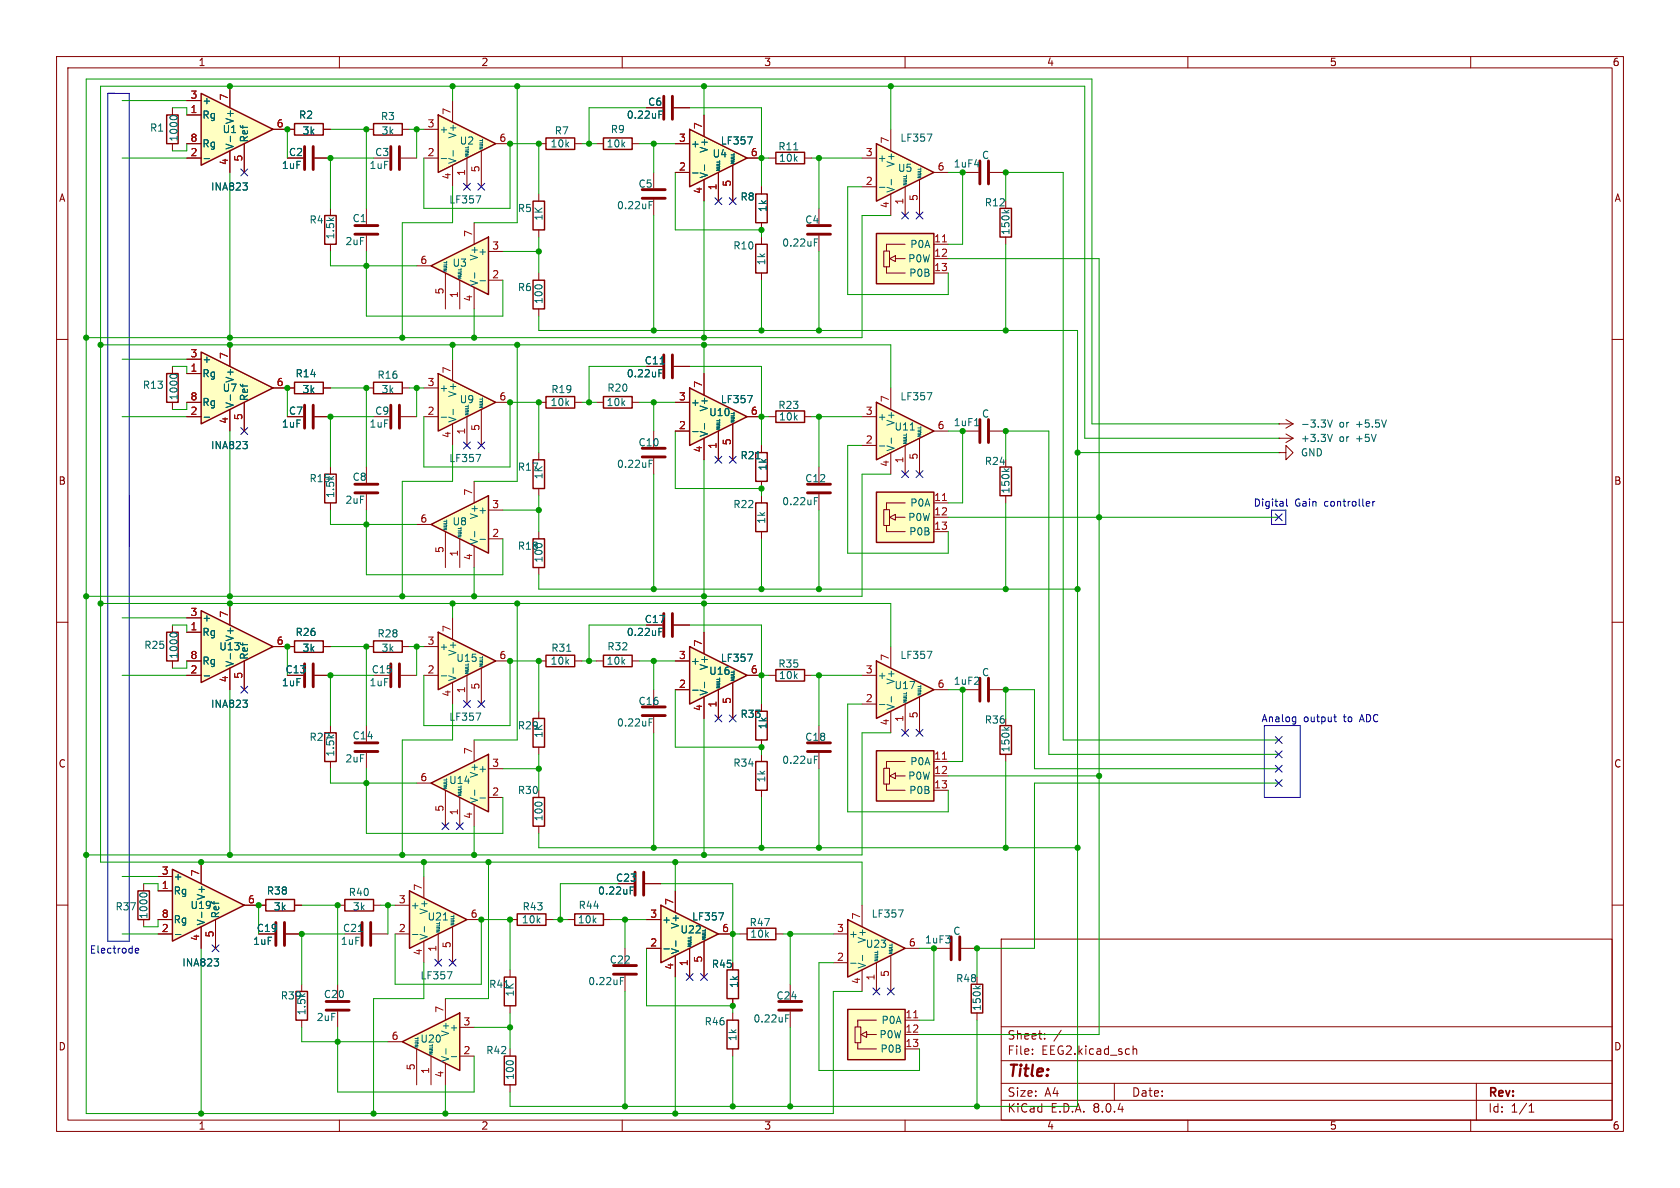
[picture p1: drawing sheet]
<svg xmlns="http://www.w3.org/2000/svg" width="297mm" height="210mm" viewBox="0 0 297 210" stroke-linecap="round" stroke-linejoin="round" font-family="sans-serif">
<defs><g id="words">
<text font-size="2.8" fill="#840000" x="178" y="190.9">Title:</text>
<g font-size="2.1" fill="#840000">
<text x="178" y="184">Sheet:</text>
<text x="178" y="186.7">File:</text>
<text x="184.1" y="186.7">EEG2.kicad_sch</text>
<text x="178" y="196.9">KiCad</text>
<text x="178" y="194.1">Size:</text>
<text x="184.7" y="194.1">A4</text>
<text x="185.7" y="196.9">E.D.A.</text>
<text x="193.3" y="196.9">8.0.4</text>
<text x="200" y="194.1">Date:</text>
<text x="263" y="194.3">Rev:</text>
<text x="263" y="196.9">Id:</text>
<text x="267.1" y="196.9">1/1</text>
</g>
<g font-size="1.8" fill="#840000">
<text x="35" y="11.9">1</text>
<text x="85" y="11.9">2</text>
<text x="135" y="11.9">3</text>
<text x="185" y="11.9">4</text>
<text x="235" y="11.9">5</text>
<text x="285" y="11.9">6</text>
<text x="114.5" y="18.9">C6</text>
<text x="51" y="27.8">C2</text>
<text x="10.3" y="35.9">A</text>
<text x="285.3" y="35.9">A</text>
<text x="113.9" y="64.6">C11</text>
<text x="51" y="73.5">C7</text>
<text x="10.3" y="85.9">B</text>
<text x="285.3" y="85.9">B</text>
<text x="113.9" y="110.3">C17</text>
<text x="50.4" y="119.2">C13</text>
<text x="10.3" y="135.9">C</text>
<text x="285.3" y="135.9">C</text>
<text x="108.8" y="156.1">C23</text>
<text x="45.3" y="164.9">C19</text>
<text x="10.3" y="185.9">D</text>
<text x="285.3" y="185.9">D</text>
<text x="35" y="199.9">1</text>
<text x="85" y="199.9">2</text>
<text x="135" y="199.9">3</text>
<text x="185" y="199.9">4</text>
<text x="235" y="199.9">5</text>
<text x="285" y="199.9">6</text>
</g>
<g font-size="1.8" fill="#a90000">
<text x="33.6" y="17.5">3</text>
<text x="40.4" y="17.9" transform="rotate(-90 40.4 17.9)">7</text>
<text x="33.6" y="20.1">1</text>
<text x="48.8" y="22.6">6</text>
<text x="75.5" y="22.6">3</text>
<text x="79.8" y="20.4" transform="rotate(-90 79.8 20.4)">7</text>
<text x="124.2" y="22.9" transform="rotate(-90 124.2 22.9)">7</text>
<text x="33.6" y="27.7">2</text>
<text x="33.6" y="25.1">8</text>
<text x="40.4" y="29.3" transform="rotate(-90 40.4 29.3)">4</text>
<text x="42.9" y="28.6" transform="rotate(-90 42.9 28.6)">5</text>
<text x="75.5" y="27.7">2</text>
<text x="88.2" y="25.1">6</text>
<text x="119.9" y="25.1">3</text>
<text x="132.6" y="27.7">6</text>
<text x="153" y="27.7">3</text>
<text x="157.2" y="25.5" transform="rotate(-90 157.2 25.5)">7</text>
<text x="79.8" y="31.8" transform="rotate(-90 79.8 31.8)">4</text>
<text x="82.3" y="31.2" transform="rotate(-90 82.3 31.2)">1</text>
<text x="84.8" y="30.6" transform="rotate(-90 84.8 30.6)">5</text>
<text x="119.9" y="30.2">2</text>
<text x="124.2" y="34.4" transform="rotate(-90 124.2 34.4)">4</text>
<text x="126.7" y="33.7" transform="rotate(-90 126.7 33.7)">1</text>
<text x="129.3" y="33.1" transform="rotate(-90 129.3 33.1)">5</text>
<text x="153" y="32.8">2</text>
<text x="162.3" y="35.6" transform="rotate(-90 162.3 35.6)">5</text>
<text x="165.7" y="30.2">6</text>
<text x="83.6" y="42" transform="rotate(-90 83.6 42)">7</text>
<text x="157.2" y="36.9" transform="rotate(-90 157.2 36.9)">4</text>
<text x="159.8" y="36.3" transform="rotate(-90 159.8 36.3)">1</text>
<text x="74.2" y="46.7">6</text>
<text x="86.9" y="44.2">3</text>
<text x="165.1" y="42.9">11</text>
<text x="165.1" y="45.5">12</text>
<text x="78.5" y="52.1" transform="rotate(-90 78.5 52.1)">5</text>
<text x="81" y="52.8" transform="rotate(-90 81 52.8)">1</text>
<text x="83.6" y="53.4" transform="rotate(-90 83.6 53.4)">4</text>
<text x="86.9" y="49.3">2</text>
<text x="165.1" y="48">13</text>
<text x="33.6" y="65.8">1</text>
<text x="33.6" y="63.2">3</text>
<text x="40.4" y="63.6" transform="rotate(-90 40.4 63.6)">7</text>
<text x="33.6" y="70.9">8</text>
<text x="48.8" y="68.3">6</text>
<text x="75.5" y="68.3">3</text>
<text x="79.8" y="66.1" transform="rotate(-90 79.8 66.1)">7</text>
<text x="88.2" y="70.9">6</text>
<text x="119.9" y="70.9">3</text>
<text x="124.2" y="68.7" transform="rotate(-90 124.2 68.7)">7</text>
<text x="157.2" y="71.2" transform="rotate(-90 157.2 71.2)">7</text>
<text x="33.6" y="73.4">2</text>
<text x="40.4" y="75" transform="rotate(-90 40.4 75)">4</text>
<text x="42.9" y="74.4" transform="rotate(-90 42.9 74.4)">5</text>
<text x="75.5" y="73.4">2</text>
<text x="79.8" y="77.5" transform="rotate(-90 79.8 77.5)">4</text>
<text x="82.3" y="76.9" transform="rotate(-90 82.3 76.9)">1</text>
<text x="84.8" y="76.3" transform="rotate(-90 84.8 76.3)">5</text>
<text x="119.9" y="75.9">2</text>
<text x="132.6" y="73.4">6</text>
<text x="153" y="73.4">3</text>
<text x="165.7" y="75.9">6</text>
<text x="124.2" y="80.1" transform="rotate(-90 124.2 80.1)">4</text>
<text x="126.7" y="79.4" transform="rotate(-90 126.7 79.4)">1</text>
<text x="129.3" y="78.8" transform="rotate(-90 129.3 78.8)">5</text>
<text x="153" y="78.5">2</text>
<text x="157.2" y="82.6" transform="rotate(-90 157.2 82.6)">4</text>
<text x="159.8" y="82" transform="rotate(-90 159.8 82)">1</text>
<text x="162.3" y="81.4" transform="rotate(-90 162.3 81.4)">5</text>
<text x="83.6" y="87.7" transform="rotate(-90 83.6 87.7)">7</text>
<text x="86.9" y="89.9">3</text>
<text x="165.1" y="88.6">11</text>
<text x="74.2" y="92.5">6</text>
<text x="86.9" y="95">2</text>
<text x="165.1" y="91.2">12</text>
<text x="165.1" y="93.7">13</text>
<text x="78.5" y="97.9" transform="rotate(-90 78.5 97.9)">5</text>
<text x="81" y="98.5" transform="rotate(-90 81 98.5)">1</text>
<text x="83.6" y="99.1" transform="rotate(-90 83.6 99.1)">4</text>
<text x="33.6" y="111.5">1</text>
<text x="33.6" y="109">3</text>
<text x="40.4" y="109.3" transform="rotate(-90 40.4 109.3)">7</text>
<text x="79.8" y="111.8" transform="rotate(-90 79.8 111.8)">7</text>
<text x="33.6" y="119.1">2</text>
<text x="33.6" y="116.6">8</text>
<text x="48.8" y="114">6</text>
<text x="75.5" y="119.1">2</text>
<text x="75.5" y="114">3</text>
<text x="88.2" y="116.6">6</text>
<text x="119.9" y="116.6">3</text>
<text x="124.2" y="114.4" transform="rotate(-90 124.2 114.4)">7</text>
<text x="132.6" y="119.1">6</text>
<text x="153" y="119.1">3</text>
<text x="157.2" y="116.9" transform="rotate(-90 157.2 116.9)">7</text>
<text x="40.4" y="120.7" transform="rotate(-90 40.4 120.7)">4</text>
<text x="42.9" y="120.1" transform="rotate(-90 42.9 120.1)">5</text>
<text x="79.8" y="123.3" transform="rotate(-90 79.8 123.3)">4</text>
<text x="82.3" y="122.6" transform="rotate(-90 82.3 122.6)">1</text>
<text x="84.8" y="122" transform="rotate(-90 84.8 122)">5</text>
<text x="119.9" y="121.7">2</text>
<text x="124.2" y="125.8" transform="rotate(-90 124.2 125.8)">4</text>
<text x="126.7" y="125.2" transform="rotate(-90 126.7 125.2)">1</text>
<text x="129.3" y="124.5" transform="rotate(-90 129.3 124.5)">5</text>
<text x="153" y="124.2">2</text>
<text x="165.7" y="121.7">6</text>
<text x="157.2" y="128.3" transform="rotate(-90 157.2 128.3)">4</text>
<text x="159.8" y="127.7" transform="rotate(-90 159.8 127.7)">1</text>
<text x="162.3" y="127.1" transform="rotate(-90 162.3 127.1)">5</text>
<text x="83.6" y="133.4" transform="rotate(-90 83.6 133.4)">7</text>
<text x="86.9" y="135.6">3</text>
<text x="165.1" y="134.4">11</text>
<text x="165.1" y="136.9">12</text>
<text x="74.2" y="138.2">6</text>
<text x="78.5" y="143.6" transform="rotate(-90 78.5 143.6)">5</text>
<text x="86.9" y="140.7">2</text>
<text x="165.1" y="139.4">13</text>
<text x="81" y="144.2" transform="rotate(-90 81 144.2)">1</text>
<text x="83.6" y="144.9" transform="rotate(-90 83.6 144.9)">4</text>
<text x="28.5" y="154.7">3</text>
<text x="35.3" y="155" transform="rotate(-90 35.3 155)">7</text>
<text x="28.5" y="157.2">1</text>
<text x="43.7" y="159.8">6</text>
<text x="70.4" y="159.8">3</text>
<text x="74.7" y="157.6" transform="rotate(-90 74.7 157.6)">7</text>
<text x="119.1" y="160.1" transform="rotate(-90 119.1 160.1)">7</text>
<text x="28.5" y="164.8">2</text>
<text x="28.5" y="162.3">8</text>
<text x="35.3" y="166.4" transform="rotate(-90 35.3 166.4)">4</text>
<text x="37.8" y="165.8" transform="rotate(-90 37.8 165.8)">5</text>
<text x="70.4" y="164.8">2</text>
<text x="79.8" y="167.7" transform="rotate(-90 79.8 167.7)">5</text>
<text x="83.1" y="162.3">6</text>
<text x="114.9" y="167.4">2</text>
<text x="114.9" y="162.3">3</text>
<text x="127.6" y="164.8">6</text>
<text x="147.9" y="164.8">3</text>
<text x="152.1" y="162.6" transform="rotate(-90 152.1 162.6)">7</text>
<text x="160.6" y="167.4">6</text>
<text x="74.7" y="169" transform="rotate(-90 74.7 169)">4</text>
<text x="77.2" y="168.3" transform="rotate(-90 77.2 168.3)">1</text>
<text x="119.1" y="171.5" transform="rotate(-90 119.1 171.5)">4</text>
<text x="121.7" y="170.9" transform="rotate(-90 121.7 170.9)">1</text>
<text x="124.2" y="170.3" transform="rotate(-90 124.2 170.3)">5</text>
<text x="147.9" y="169.9">2</text>
<text x="154.7" y="173.4" transform="rotate(-90 154.7 173.4)">1</text>
<text x="157.2" y="172.8" transform="rotate(-90 157.2 172.8)">5</text>
<text x="78.5" y="179.1" transform="rotate(-90 78.5 179.1)">7</text>
<text x="152.1" y="174.1" transform="rotate(-90 152.1 174.1)">4</text>
<text x="69.1" y="183.9">6</text>
<text x="81.8" y="181.4">3</text>
<text x="160" y="180.1">11</text>
<text x="160" y="182.6">12</text>
<text x="160" y="185.2">13</text>
<text x="73.4" y="189.3" transform="rotate(-90 73.4 189.3)">5</text>
<text x="75.9" y="189.9" transform="rotate(-90 75.9 189.9)">1</text>
<text x="78.5" y="190.6" transform="rotate(-90 78.5 190.6)">4</text>
<text x="81.8" y="186.4">2</text>
</g>
<g font-size="1.8" fill="#006464">
<text x="26.4" y="23.5">R1</text>
<text x="35.7" y="21.2">Rg</text>
<text x="35.7" y="18.6">+</text>
<text x="39.3" y="23.7">U1</text>
<text x="41.5" y="22" transform="rotate(-90 41.5 22)">V+</text>
<text x="52.8" y="21.2">R2</text>
<text x="53.4" y="24">3k</text>
<text x="67.2" y="21.4">R3</text>
<text x="67.4" y="24">3k</text>
<text x="77.6" y="23.7">+</text>
<text x="98" y="24">R7</text>
<text x="107.9" y="23.7">R9</text>
<text x="110.7" y="21.2">0.22uF</text>
<text x="31.6" y="25.1" transform="rotate(-90 31.6 25.1)">1000</text>
<text x="35.7" y="26.3">Rg</text>
<text x="41.5" y="26.5" transform="rotate(-90 41.5 26.5)">V-</text>
<text x="44" y="25.3" transform="rotate(-90 44 25.3)">Ref</text>
<text x="66.2" y="27.8">C3</text>
<text x="80.9" y="29.1" transform="rotate(-90 80.9 29.1)">V-</text>
<text x="80.9" y="24.6" transform="rotate(-90 80.9 24.6)">V+</text>
<text x="81.2" y="25.8">U2</text>
<text x="97.2" y="26.3">10k</text>
<text x="107.1" y="26.3">10k</text>
<text x="122" y="26.3">+</text>
<text x="125.3" y="27.1" transform="rotate(-90 125.3 27.1)">V+</text>
<text x="125.9" y="28">U4</text>
<text x="127.3" y="25.8">LF357</text>
<text x="137.5" y="26.8">R11</text>
<text x="137.6" y="28.8">10k</text>
<text x="155.1" y="28.8">+</text>
<text x="158.3" y="29.7" transform="rotate(-90 158.3 29.7)">V+</text>
<text x="159.1" y="25.2">LF357</text>
<text x="168.5" y="29.8">1uF4</text>
<text x="173.5" y="28.3">C</text>
<text x="37.2" y="33.9">INA823</text>
<text x="49.7" y="30.1">1uF</text>
<text x="65.2" y="30.1">1uF</text>
<text x="112.8" y="33.4">C5</text>
<text x="125.3" y="31.6" transform="rotate(-90 125.3 31.6)">V-</text>
<text x="130.8" y="35.7">R8</text>
<text x="158.3" y="34.2" transform="rotate(-90 158.3 34.2)">V-</text>
<text x="158.6" y="30.6">U5</text>
<text x="54.6" y="39.7">R4</text>
<text x="62.2" y="39.5">C1</text>
<text x="79.3" y="36.2">LF357</text>
<text x="91.4" y="37.7">R5</text>
<text x="96.1" y="39.1" transform="rotate(-90 96.1 39.1)">1K</text>
<text x="109" y="37.2">0.22uF</text>
<text x="135.7" y="37.6" transform="rotate(-90 135.7 37.6)">1k</text>
<text x="142.2" y="39.7">C4</text>
<text x="174" y="36.7">R12</text>
<text x="178.7" y="41.6" transform="rotate(-90 178.7 41.6)">150k</text>
<text x="59.3" y="42.4" transform="rotate(-90 59.3 42.4)">1.5k</text>
<text x="61" y="43.5">2uF</text>
<text x="79.9" y="47.3">U3</text>
<text x="84.5" y="45.3">+</text>
<text x="84.7" y="46.2" transform="rotate(-90 84.7 46.2)">V+</text>
<text x="129.5" y="44.3">R10</text>
<text x="135.5" y="47" transform="rotate(-90 135.5 47)">1k</text>
<text x="138.2" y="43.8">0.22uF</text>
<text x="160.5" y="46.6">P0W</text>
<text x="160.8" y="44">P0A</text>
<text x="84.7" y="50.7" transform="rotate(-90 84.7 50.7)">V-</text>
<text x="91.4" y="51.7">R6</text>
<text x="96.1" y="53.8" transform="rotate(-90 96.1 53.8)">100</text>
<text x="160.6" y="49.1">P0B</text>
<text x="35.7" y="64.4">+</text>
<text x="25.2" y="68.9">R13</text>
<text x="31.6" y="70.9" transform="rotate(-90 31.6 70.9)">1000</text>
<text x="35.7" y="66.9">Rg</text>
<text x="35.7" y="72">Rg</text>
<text x="39.3" y="69.4">U7</text>
<text x="41.5" y="67.8" transform="rotate(-90 41.5 67.8)">V+</text>
<text x="44" y="71" transform="rotate(-90 44 71)">Ref</text>
<text x="52.2" y="66.9">R14</text>
<text x="53.4" y="69.7">3k</text>
<text x="66.6" y="67.2">R16</text>
<text x="67.4" y="69.7">3k</text>
<text x="77.6" y="69.4">+</text>
<text x="80.9" y="70.3" transform="rotate(-90 80.9 70.3)">V+</text>
<text x="81.2" y="71.5">U9</text>
<text x="97.2" y="72">10k</text>
<text x="97.4" y="69.7">R19</text>
<text x="107.1" y="72">10k</text>
<text x="107.3" y="69.4">R20</text>
<text x="110.7" y="66.9">0.22uF</text>
<text x="122" y="72">+</text>
<text x="127.3" y="71.5">LF357</text>
<text x="159.1" y="71">LF357</text>
<text x="41.5" y="72.3" transform="rotate(-90 41.5 72.3)">V-</text>
<text x="49.7" y="75.8">1uF</text>
<text x="65.2" y="75.8">1uF</text>
<text x="66.2" y="73.5">C9</text>
<text x="80.9" y="74.8" transform="rotate(-90 80.9 74.8)">V-</text>
<text x="125.3" y="73.8">U10</text>
<text x="125.3" y="77.3" transform="rotate(-90 125.3 77.3)">V-</text>
<text x="125.3" y="72.8" transform="rotate(-90 125.3 72.8)">V+</text>
<text x="137.5" y="72.5">R23</text>
<text x="137.6" y="74.5">10k</text>
<text x="155.1" y="74.5">+</text>
<text x="158" y="76.3">U11</text>
<text x="158.3" y="75.4" transform="rotate(-90 158.3 75.4)">V+</text>
<text x="168.5" y="75.5">1uF1</text>
<text x="173.5" y="74">C</text>
<text x="229.9" y="75.8">-3.3V</text>
<text x="236.7" y="75.8">or</text>
<text x="239.8" y="75.8">+5.5V</text>
<text x="37.2" y="79.6">INA823</text>
<text x="79.3" y="81.9">LF357</text>
<text x="91.4" y="83.4">R17</text>
<text x="109" y="82.9">0.22uF</text>
<text x="112.8" y="79.1">C10</text>
<text x="130.8" y="81.4">R21</text>
<text x="135.7" y="83.3" transform="rotate(-90 135.7 83.3)">1k</text>
<text x="158.3" y="79.9" transform="rotate(-90 158.3 79.9)">V-</text>
<text x="174" y="82.4">R24</text>
<text x="229.9" y="80.9">GND</text>
<text x="229.9" y="78.3">+3.3V</text>
<text x="236.7" y="78.3">or</text>
<text x="239.8" y="78.3">+5V</text>
<text x="54.6" y="85.4">R15</text>
<text x="59.3" y="88.1" transform="rotate(-90 59.3 88.1)">1.5k</text>
<text x="61" y="89.3">2uF</text>
<text x="62.2" y="85.2">C8</text>
<text x="96.1" y="84.8" transform="rotate(-90 96.1 84.8)">1K</text>
<text x="138.2" y="89.5">0.22uF</text>
<text x="142.2" y="85.4">C12</text>
<text x="160.8" y="89.8">P0A</text>
<text x="178.7" y="87.4" transform="rotate(-90 178.7 87.4)">150k</text>
<text x="79.9" y="93.1">U8</text>
<text x="84.5" y="91">+</text>
<text x="84.7" y="91.9" transform="rotate(-90 84.7 91.9)">V+</text>
<text x="129.5" y="90">R22</text>
<text x="135.5" y="92.7" transform="rotate(-90 135.5 92.7)">1k</text>
<text x="160.5" y="92.3">P0W</text>
<text x="160.6" y="94.8">P0B</text>
<text x="84.7" y="96.4" transform="rotate(-90 84.7 96.4)">V-</text>
<text x="91.4" y="97.4">R18</text>
<text x="96.1" y="99.6" transform="rotate(-90 96.1 99.6)">100</text>
<text x="35.7" y="112.6">Rg</text>
<text x="35.7" y="110.1">+</text>
<text x="41.5" y="113.5" transform="rotate(-90 41.5 113.5)">V+</text>
<text x="52.2" y="112.6">R26</text>
<text x="66.6" y="112.9">R28</text>
<text x="110.7" y="112.6">0.22uF</text>
<text x="25.4" y="114.9">R25</text>
<text x="31.6" y="116.6" transform="rotate(-90 31.6 116.6)">1000</text>
<text x="35.7" y="117.7">Rg</text>
<text x="38.7" y="115.2">U13</text>
<text x="41.5" y="118" transform="rotate(-90 41.5 118)">V-</text>
<text x="44" y="116.7" transform="rotate(-90 44 116.7)">Ref</text>
<text x="53.4" y="115.4">3k</text>
<text x="65.6" y="119.2">C15</text>
<text x="67.4" y="115.4">3k</text>
<text x="77.6" y="115.2">+</text>
<text x="80.6" y="117.2">U15</text>
<text x="80.9" y="116" transform="rotate(-90 80.9 116)">V+</text>
<text x="97.2" y="117.7">10k</text>
<text x="97.4" y="115.4">R31</text>
<text x="107.1" y="117.7">10k</text>
<text x="107.3" y="115.2">R32</text>
<text x="122" y="117.7">+</text>
<text x="125.3" y="119.5">U16</text>
<text x="125.3" y="118.6" transform="rotate(-90 125.3 118.6)">V+</text>
<text x="127.3" y="117.2">LF357</text>
<text x="137.5" y="118.2">R35</text>
<text x="159.1" y="116.7">LF357</text>
<text x="173.5" y="119.7">C</text>
<text x="37.2" y="125.3">INA823</text>
<text x="49.7" y="121.5">1uF</text>
<text x="65.2" y="121.5">1uF</text>
<text x="80.9" y="120.5" transform="rotate(-90 80.9 120.5)">V-</text>
<text x="112.8" y="124.8">C16</text>
<text x="125.3" y="123.1" transform="rotate(-90 125.3 123.1)">V-</text>
<text x="137.6" y="120.2">10k</text>
<text x="155.1" y="120.2">+</text>
<text x="158" y="122">U17</text>
<text x="158.3" y="125.6" transform="rotate(-90 158.3 125.6)">V-</text>
<text x="158.3" y="121.1" transform="rotate(-90 158.3 121.1)">V+</text>
<text x="168.5" y="121.3">1uF2</text>
<text x="54.6" y="131.2">R27</text>
<text x="62.2" y="130.9">C14</text>
<text x="79.3" y="127.6">LF357</text>
<text x="91.4" y="129.1">R29</text>
<text x="96.1" y="130.5" transform="rotate(-90 96.1 130.5)">1K</text>
<text x="109" y="128.6">0.22uF</text>
<text x="130.8" y="127.1">R33</text>
<text x="135.7" y="129" transform="rotate(-90 135.7 129)">1k</text>
<text x="142.2" y="131.2">C18</text>
<text x="174" y="128.1">R36</text>
<text x="59.3" y="133.8" transform="rotate(-90 59.3 133.8)">1.5k</text>
<text x="61" y="135">2uF</text>
<text x="84.5" y="136.8">+</text>
<text x="84.7" y="137.6" transform="rotate(-90 84.7 137.6)">V+</text>
<text x="129.5" y="135.7">R34</text>
<text x="138.2" y="135.2">0.22uF</text>
<text x="160.8" y="135.5">P0A</text>
<text x="178.7" y="133.1" transform="rotate(-90 178.7 133.1)">150k</text>
<text x="79.3" y="138.8">U14</text>
<text x="84.7" y="142.1" transform="rotate(-90 84.7 142.1)">V-</text>
<text x="91.4" y="140.6">R30</text>
<text x="135.5" y="138.4" transform="rotate(-90 135.5 138.4)">1k</text>
<text x="160.5" y="138">P0W</text>
<text x="160.6" y="140.6">P0B</text>
<text x="96.1" y="145.3" transform="rotate(-90 96.1 145.3)">100</text>
<text x="30.6" y="155.8">+</text>
<text x="20.3" y="161.1">R37</text>
<text x="30.6" y="158.3">Rg</text>
<text x="33.6" y="160.9">U19</text>
<text x="36.4" y="159.2" transform="rotate(-90 36.4 159.2)">V+</text>
<text x="47.1" y="158.3">R38</text>
<text x="48.3" y="161.1">3k</text>
<text x="61.6" y="158.6">R40</text>
<text x="62.3" y="161.1">3k</text>
<text x="72.5" y="160.9">+</text>
<text x="75.8" y="161.7" transform="rotate(-90 75.8 161.7)">V+</text>
<text x="92.3" y="161.1">R43</text>
<text x="102.2" y="160.9">R44</text>
<text x="105.6" y="158.3">0.22uF</text>
<text x="26.3" y="162.6" transform="rotate(-90 26.3 162.6)">1000</text>
<text x="30.6" y="163.4">Rg</text>
<text x="36.4" y="163.7" transform="rotate(-90 36.4 163.7)">V-</text>
<text x="39" y="162.4" transform="rotate(-90 39 162.4)">Ref</text>
<text x="44.7" y="167.2">1uF</text>
<text x="60.2" y="167.2">1uF</text>
<text x="60.5" y="164.9">C21</text>
<text x="75.5" y="162.9">U21</text>
<text x="75.8" y="166.2" transform="rotate(-90 75.8 166.2)">V-</text>
<text x="92.2" y="163.4">10k</text>
<text x="102.1" y="163.4">10k</text>
<text x="117" y="163.4">+</text>
<text x="120.2" y="165.2">U22</text>
<text x="120.2" y="164.3" transform="rotate(-90 120.2 164.3)">V+</text>
<text x="122.2" y="162.9">LF357</text>
<text x="132.4" y="163.9">R47</text>
<text x="132.5" y="166">10k</text>
<text x="150" y="166">+</text>
<text x="153" y="167.7">U23</text>
<text x="153.3" y="166.8" transform="rotate(-90 153.3 166.8)">V+</text>
<text x="154" y="162.4">LF357</text>
<text x="163.4" y="167">1uF3</text>
<text x="168.4" y="165.5">C</text>
<text x="32.1" y="171">INA823</text>
<text x="74.2" y="173.3">LF357</text>
<text x="107.7" y="170.5">C22</text>
<text x="120.2" y="168.8" transform="rotate(-90 120.2 168.8)">V-</text>
<text x="125.7" y="171.3">R45</text>
<text x="153.3" y="171.3" transform="rotate(-90 153.3 171.3)">V-</text>
<text x="168.9" y="173.8">R48</text>
<text x="49.5" y="176.9">R39</text>
<text x="54.2" y="179.6" transform="rotate(-90 54.2 179.6)">1.5k</text>
<text x="57.2" y="176.6">C20</text>
<text x="86.4" y="174.9">R41</text>
<text x="91" y="176.3" transform="rotate(-90 91 176.3)">1K</text>
<text x="103.9" y="174.3">0.22uF</text>
<text x="130.7" y="174.7" transform="rotate(-90 130.7 174.7)">1k</text>
<text x="137.2" y="176.9">C24</text>
<text x="173.6" y="178.8" transform="rotate(-90 173.6 178.8)">150k</text>
<text x="55.9" y="180.7">2uF</text>
<text x="74.2" y="184.5">U20</text>
<text x="79.4" y="182.5">+</text>
<text x="79.6" y="183.3" transform="rotate(-90 79.6 183.3)">V+</text>
<text x="124.5" y="181.5">R46</text>
<text x="130.4" y="184.1" transform="rotate(-90 130.4 184.1)">1k</text>
<text x="133.1" y="180.9">0.22uF</text>
<text x="155.4" y="183.7">P0W</text>
<text x="155.7" y="181.2">P0A</text>
<text x="79.6" y="187.8" transform="rotate(-90 79.6 187.8)">V-</text>
<text x="85.9" y="186.5">R42</text>
<text x="91" y="191" transform="rotate(-90 91 191)">100</text>
<text x="155.6" y="186.3">P0B</text>
</g>
<g font-size="1.8" fill="#0000c2">
<text x="221.5" y="89.8">Digital</text>
<text x="228.9" y="89.8">Gain</text>
<text x="234.2" y="89.8">controller</text>
<text x="222.9" y="127.9">Analog</text>
<text x="230.4" y="127.9">output</text>
<text x="237.7" y="127.9">to</text>
<text x="240.7" y="127.9">ADC</text>
<text x="15.8" y="168.8">Electrode</text>
</g>
<g font-size=".7" fill="#006464">
<text x="83" y="27.8" transform="rotate(-90 83 27.8)">NULL</text>
<text x="85.6" y="26.5" transform="rotate(-90 85.6 26.5)">NULL</text>
<text x="130" y="29.1" transform="rotate(-90 130 29.1)">NULL</text>
<text x="127.5" y="30.4" transform="rotate(-90 127.5 30.4)">NULL</text>
<text x="160.5" y="32.9" transform="rotate(-90 160.5 32.9)">NULL</text>
<text x="163" y="31.6" transform="rotate(-90 163 31.6)">NULL</text>
<text x="79.2" y="48.1" transform="rotate(-90 79.2 48.1)">NULL</text>
<text x="81.8" y="49.4" transform="rotate(-90 81.8 49.4)">NULL</text>
<text x="83" y="73.5" transform="rotate(-90 83 73.5)">NULL</text>
<text x="85.6" y="72.3" transform="rotate(-90 85.6 72.3)">NULL</text>
<text x="127.5" y="76.1" transform="rotate(-90 127.5 76.1)">NULL</text>
<text x="130" y="74.8" transform="rotate(-90 130 74.8)">NULL</text>
<text x="163" y="77.3" transform="rotate(-90 163 77.3)">NULL</text>
<text x="160.5" y="78.6" transform="rotate(-90 160.5 78.6)">NULL</text>
<text x="79.2" y="93.9" transform="rotate(-90 79.2 93.9)">NULL</text>
<text x="81.8" y="95.1" transform="rotate(-90 81.8 95.1)">NULL</text>
<text x="83" y="119.3" transform="rotate(-90 83 119.3)">NULL</text>
<text x="85.6" y="118" transform="rotate(-90 85.6 118)">NULL</text>
<text x="127.5" y="121.8" transform="rotate(-90 127.5 121.8)">NULL</text>
<text x="130" y="120.5" transform="rotate(-90 130 120.5)">NULL</text>
<text x="160.5" y="124.3" transform="rotate(-90 160.5 124.3)">NULL</text>
<text x="163" y="123.1" transform="rotate(-90 163 123.1)">NULL</text>
<text x="79.2" y="139.6" transform="rotate(-90 79.2 139.6)">NULL</text>
<text x="81.8" y="140.8" transform="rotate(-90 81.8 140.8)">NULL</text>
<text x="78" y="165" transform="rotate(-90 78 165)">NULL</text>
<text x="80.5" y="163.7" transform="rotate(-90 80.5 163.7)">NULL</text>
<text x="122.4" y="167.5" transform="rotate(-90 122.4 167.5)">NULL</text>
<text x="124.9" y="166.2" transform="rotate(-90 124.9 166.2)">NULL</text>
<text x="155.4" y="170.1" transform="rotate(-90 155.4 170.1)">NULL</text>
<text x="158" y="168.8" transform="rotate(-90 158 168.8)">NULL</text>
<text x="74.1" y="185.3" transform="rotate(-90 74.1 185.3)">NULL</text>
<text x="76.7" y="186.6" transform="rotate(-90 76.7 186.6)">NULL</text>
</g>
</g></defs>
<g fill="none" stroke="#840000" stroke-width=".18">
<path d="M10 10h277v190h-277zM12 12h273v186h-273zM60 10v2M110 10v2M160 10v2M210 10v2M260 10v2M10 60h2M285 60h2M226.1 77.5h.1M226.1 74.9h.1M226.1 77.5h2.5"/>
<path d="M226.1 74.9h2.5M227.3 76.7l1.3 .8M227.3 74.2l1.3 .7M228.6 77.5l-1.3 .7M228.6 74.9l-1.3 .8M226.1 80h1.2v-1.3l1.3 1.3-1.3 1.3v-1.3M226.1 80h.1M10 110h2M285 110h2M10 160h2M285 160h2M177 166h108v32h-108z"/>
<path d="M60 198v2M110 198v2M160 198v2M177 194.5h108M177 191.5h108M177 187.5h108M177 181.5h108M182.5 186.3v.1M182.5 185.5v.1M184.7 183.6v.1M184.7 182.8v.1M187.6 182.1l-1.3 2"/>
<path d="M197 191.5v3M200.3 184.9v1.5M200.3 185.5l.2-.1 .4 .1 .1 .9M210 198v2M260 198v2M261 191.5v6.5M270.3 196.6h.9M270.3 195.5l.4-.4v1.5"/>
</g>
<path d="M234.7 74.2l.4 1.3 .4-1.3M235.5 76.8l-.4 1.2M245.1 74.2l-.4 1.3" fill="none" stroke="#006464" stroke-width=".18"/>
<path d="M35.6 108l12.7 6.3-12.7 6.4z" fill="#ffffc2"/>
<path d="M106.7 24.4h5.1v2h-5.1zM176.8 82.6h2v5h-2zM29.5 111.8h2v5h-2zM35.6 108l12.7 6.3-12.7 6.4zM57.4 129.5h2v5.1h-2zM133.6 134.6h2v5.1h-2zM133.6 125.7h2v5.1h-2zM47 159h5.1v2h-5.1zM52.3 175.3h2.1v5h-2.1zM128.5 171.5h2.1v5h-2.1zM128.5 180.3h2.1v5.1h-2.1z" fill="none" stroke="#840000" stroke-width=".25"/>
<g fill="none" stroke="#840000" stroke-width=".18">
<path d="M119.1 19.1h2.8M105.4 25.4h1.3M111.8 25.4h1.2M115.6 30.5v2.8M115.6 35.3v2.8M177.8 87.6v1.3M30.5 110.5v1.3M30.5 116.8v1.3M33 111.8h2.6M33 119.4h2.6M33 109.2h2.6M33 116.8h2.6"/>
<path d="M40.6 106.7v3.8M40.6 118.1v3.8M43.2 116.8v5.1M48.3 114.3h2.5M58.4 128.3v1.2M58.4 134.6v1.3M134.6 124.5v1.2M134.6 130.8v1.3M134.6 133.4v1.2M134.6 139.7v1.3M144.8 128.3v2.8M144.8 133.1v2.8"/>
<path d="M45.7 160h1.3M50.5 165.1h2.8M52.1 160h1.2M53.3 174v1.3M59.7 174v2.8M59.7 178.8v2.8M129.5 170.2v1.3M129.5 176.5v1.3M129.5 179.1v1.2M139.7 174v2.8M139.7 178.8v2.8M53.3 180.3v1.3"/>
<path d="M129.5 185.4v1.3"/>
</g>
<g fill="none" stroke="#006464" stroke-width=".18">
<path d="M116.5 19.6h.6M114.8 36.2h.4M114.8 35.6h.6M116.5 20.2h.4M177.5 82.8l.5 .5M178.4 82.8l-.5 .4M30 112.2a.79 .79 0 0 1 1.3 0M36.1 119.5h1M40.7 115.5v1M42.9 123.8h.8l-.4 .5M43.7 124.4v.5M144 134.3h.4"/>
<path d="M144 133.7h.6M138.9 179.4h.6M138.9 180h.4"/>
</g>
<path d="M117.3 17v4.1M118.9 17v4.1M113.5 35.1h4.1M113.5 33.5h4.1M142.7 132.8h4.1M142.7 131.3h4.1M48.8 163.1v4M50.3 163.1v4M57.7 178.6h4M57.7 177h4M137.7 178.6h4M137.7 177h4" fill="none" stroke="#840000" stroke-width=".51"/>
<path d="M156.7 134.6h3.3M156.7 139.7h3.3" fill="none" stroke="#ffffc2" stroke-width=".18"/>
<g fill="#ffffc2">
<path d="M156.7 139.4v.3z"/>
<path d="M154.9 132.7h10.2v8.9h-10.2z"/>
</g>
<g fill="none" stroke="#840000" stroke-width=".18">
<path d="M156.2 135.8h1.1v2.8h-1.1zM156.7 138.6v1.1h3.3M156.7 134.8v1M157.3 137.2l1-.5v1zM158.3 137.2h1.7M160 134.6h-3.3v.3M165.1 137.2h2.5M165.1 134.6h2.5M165.1 139.7h2.5M170.2 121.9h2.8M175 121.9h2.8M177.8 127v1.3"/>
<path d="M177.8 133.4v1.2"/>
</g>
<path d="M154.9 132.7h10.2v8.9h-10.2zM176.8 128.3h2v5.1h-2z" fill="none" stroke="#840000" stroke-width=".25"/>
<path d="M166.6 134.2h.7" fill="none" stroke="#a90000" stroke-width=".18"/>
<path d="M177.5 128.6l.5 .5M178.4 128.6l-.5 .3" fill="none" stroke="#006464" stroke-width=".18"/>
<path d="M173.2 119.9v4.1M174.8 119.9v4.1" fill="none" stroke="#840000" stroke-width=".51"/>
<path d="M154.9 116.8l10.2 5.1-10.2 5.1z" fill="#ffffc2"/>
<path d="M154.9 116.8l10.2 5.1-10.2 5.1z" fill="none" stroke="#840000" stroke-width=".25"/>
<path d="M152.4 119.4h2.5M157.5 114.3v3.8M152.4 124.5h2.5M157.5 125.7v3.8M160 124.5v5M162.6 123.2v6.3M165.1 121.9h2.5" fill="none" stroke="#840000" stroke-width=".18"/>
<path d="M163.9 115.1h.8l-.5 1.3M155.5 124.6h.9M157.6 123.1v1M159.7 123.8h.5l-.5 .3h.5M159.7 123.6h.5M159.7 123.3h.5M159.7 123h.5M162.3 122.6h.5l-.5 .2h.5M162.3 122.3h.4M162.3 122h.4M162.3 121.8h.5M162.3 121.4h.5" fill="none" stroke="#006464" stroke-width=".18"/>
<path d="M30.5 153.7l12.7 6.3-12.7 6.4z" fill="#ffffc2"/>
<path d="M94.2 35.6h2.1v5h-2.1zM96.5 24.4h5.1v2h-5.1zM96.5 115.8h5.1v2.1h-5.1zM106.7 115.8h5.1v2.1h-5.1zM137.2 118.4h5v2h-5zM94.2 127h2.1v5.1h-2.1zM24.4 157.5h2v5.1h-2zM30.5 153.7l12.7 6.3-12.7 6.4zM94.2 141h2.1v5.1h-2.1zM91.4 161.5h5.1v2.1h-5.1zM101.6 161.5h5.1v2.1h-5.1z" fill="none" stroke="#840000" stroke-width=".25"/>
<g fill="none" stroke="#840000" stroke-width=".18">
<path d="M95.2 25.4h1.3M95.2 34.3v1.3M101.6 25.4h1.3M95.2 40.6v1.3M95.2 116.8h1.3M101.6 116.8h1.3M105.4 116.8h1.3M111.8 116.8h1.2M119.1 110.5h2.8M135.9 119.4h1.3M142.2 119.4h1.3M64.8 128.3v2.8"/>
<path d="M64.8 133.1v2.8M95.2 125.7v1.3M95.2 132.1v1.3M95.2 139.7v1.3M115.6 121.9v2.8M115.6 126.7v2.8M25.4 156.2v1.3M27.9 157.5h2.6M27.9 154.9h2.6M35.6 152.4v3.8M95.2 146.1v1.2M114 156.2h2.8"/>
<path d="M25.4 162.6v1.2M27.9 165.1h2.6M27.9 162.6h2.6M35.6 163.8v3.8M38.1 162.6v5M43.2 160h2.5M90.2 162.6h1.2M96.5 162.6h1.3M100.3 162.6h1.3M106.7 162.6h1.2"/>
</g>
<path d="M100.2 115.1h.7M116.5 111.7h.4M116.5 111.1h.6M114.8 127.7h.4M114.8 127.1h.6M24.7 158.2a.79 .79 0 0 1 1.3 0M111.4 157.4h.4M111.4 156.8h.6M31 165.2h1M35.7 161.2v1M37.9 169.5h.7l-.4 .5M38.6 170.1v.5" fill="none" stroke="#006464" stroke-width=".18"/>
<path d="M117.3 108.5v4M118.9 108.5v4M62.7 132.8h4.1M62.7 131.3h4.1M113.5 126.5h4.1M113.5 125h4.1M112.3 154.2v4M113.8 154.2v4" fill="none" stroke="#840000" stroke-width=".51"/>
<path d="M121.9 114.3l10.2 5.1-10.2 5.1z" fill="#ffffc2"/>
<path d="M66 21.8h5.1v2.1h-5.1zM121.9 114.3l10.2 5.1-10.2 5.1zM132.1 164.1h5.1v2h-5.1z" fill="none" stroke="#840000" stroke-width=".25"/>
<g fill="none" stroke="#840000" stroke-width=".18">
<path d="M64.8 22.9h1.2M71.1 22.9h1.3M119.4 116.8h2.5M124.5 111.8v3.8M132.1 119.4h2.5M119.4 121.9h2.5M124.5 123.2v3.8M127 121.9v5.1M129.5 120.7v6.3M110.5 167.6v2.8M110.5 172.5v2.8M130.8 165.1h1.3"/>
<path d="M137.2 165.1h1.2"/>
</g>
<g fill="none" stroke="#006464" stroke-width=".18">
<path d="M129.3 119.8h.4M129.3 119.5h.4M129.3 119.2h.5M129.3 118.8h.5M132.1 115.6h.9l-.6 1.3M122.4 122h1M124.6 120.6v1M126.7 121.3h.5l-.5 .3h.5M126.7 121h.4M126.7 120.7h.4M126.7 120.5h.5M129.3 120h.5l-.5 .3h.5"/>
<path d="M109.7 173.4h.4M109.7 172.8h.6"/>
</g>
<path d="M108.5 172.2h4M108.5 170.7h4" fill="none" stroke="#840000" stroke-width=".51"/>
<path d="M116.8 160l10.2 5.1-10.2 5.1z" fill="#ffffc2"/>
<path d="M116.8 160l10.2 5.1-10.2 5.1z" fill="none" stroke="#840000" stroke-width=".25"/>
<path d="M70.9 27.9h2.8M119.4 157.5v3.8M114.3 167.6h2.5M114.3 162.6h2.5M119.4 168.9v3.8M121.9 167.6v5.1M124.5 166.4v6.3M127 165.1h2.5" fill="none" stroke="#840000" stroke-width=".18"/>
<path d="M117.4 167.7h.9M119.5 166.3v1M121.6 167h.5l-.5 .3h.5M121.6 166.8h.5M121.6 166.5h.5M121.6 166.2h.5M124.2 165.7h.5l-.5 .3h.5M124.2 165.5h.4M124.2 165.2h.4M124.2 165h.5M124.2 164.5h.5M127.1 161.4h.8l-.5 1.2" fill="none" stroke="#006464" stroke-width=".18"/>
<path d="M69.1 25.9v4.1M70.6 25.9v4.1" fill="none" stroke="#840000" stroke-width=".51"/>
<path d="M77.5 20.3l10.1 5.1-10.1 5.1z" fill="#ffffc2"/>
<path d="M29.5 20.3h2v5.1h-2zM77.5 20.3l10.1 5.1-10.1 5.1zM94.2 49.5h2.1v5.1h-2.1zM52.1 67.6h5v2h-5zM66 67.6h5.1v2h-5.1zM57.4 83.8h2v5.1h-2zM52.1 113.3h5v2h-5zM89.2 186.7h2v5.1h-2z" fill="none" stroke="#840000" stroke-width=".25"/>
<g fill="none" stroke="#840000" stroke-width=".18">
<path d="M30.5 19.1v1.2M80 17.8v3.8M30.5 25.4v1.3M74.9 27.9h2.6M74.9 22.9h2.6M80 29.2v3.8M82.5 27.9v5.1M85.1 26.7v6.3M87.6 25.4h2.6M95.2 48.3v1.2M95.2 54.6v1.3M50.8 68.6h1.3"/>
<path d="M55.6 73.7h2.8M57.1 68.6h1.3M64.8 68.6h1.2M70.9 73.7h2.8M71.1 68.6h1.3M58.4 82.6v1.2M58.4 88.9v1.3M64.8 82.6v2.7M64.8 87.4v2.8M50.8 114.3h1.3M55.6 119.4h2.8M57.1 114.3h1.3"/>
<path d="M90.2 185.4v1.3M90.2 191.8v1.2"/>
</g>
<g fill="none" stroke="#006464" stroke-width=".18">
<path d="M30 20.7a.79 .79 0 0 1 1.3 0M78 28h1M80.1 26.6v1M82.3 27.3h.5l-.5 .3h.5M82.3 27.1h.4M82.3 26.8h.4M82.3 26.5h.5M84.1 34.6h.9l-.6 1.3M84.8 26h.5l-.5 .3h.5M84.8 25.8h.4M84.8 25.5h.4M84.8 25.3h.5"/>
<path d="M84.8 24.8h.5"/>
</g>
<path d="M53.8 71.6v4.1M55.4 71.6v4.1M69.1 71.6v4.1M70.6 71.6v4.1M62.7 87.1h4.1M62.7 85.6h4.1M53.8 117.3v4.1M55.4 117.3v4.1" fill="none" stroke="#840000" stroke-width=".51"/>
<path d="M71.1 184.2l10.2-5.1v10.1z" fill="#ffffc2"/>
<path d="M71.1 184.2l10.2-5.1v10.1z" fill="none" stroke="#840000" stroke-width=".25"/>
<path d="M78.7 176.5v3.8M68.6 184.2h2.5M73.7 185.4v6.4M76.2 186.7v5.1M78.7 188v3.8M81.3 186.7h2.5M81.3 181.6h2.5" fill="none" stroke="#840000" stroke-width=".18"/>
<path d="M73.4 184.8h.5l-.5 .3h.5M73.4 184.5h.4M73.4 184.2h.4M73.4 184h.5M73.4 183.6h.5M75.9 186.1h.5l-.5 .2h.5M75.9 185.8h.4M75.9 185.5h.4M75.9 185.3h.5M78.8 185.4v.9M79.8 186.8h1" fill="none" stroke="#006464" stroke-width=".18"/>
<path d="M121.9 22.9l10.2 5-10.2 5.1z" fill="#ffffc2"/>
<path d="M121.9 22.9l10.2 5-10.2 5.1zM137.2 72.6h5v2.1h-5z" fill="none" stroke="#840000" stroke-width=".25"/>
<path d="M119.4 30.5h2.5M119.4 25.4h2.5M124.5 20.3v3.8M124.5 31.8v3.8M127 30.5v5.1M129.5 29.2v6.4M132.1 27.9h2.5M135.9 73.7h1.3M142.2 73.7h1.3" fill="none" stroke="#840000" stroke-width=".18"/>
<path d="M122.4 30.6h1M124.6 29.2v.9M126.7 29.8h.5l-.5 .3h.5M126.7 29.6h.4M126.7 29.3h.4M126.7 29.1h.5M129.3 28.6h.5l-.5 .3h.5M129.3 28.3h.4M129.3 28h.4M129.3 27.8h.5M129.3 27.4h.5M132.1 24.2h.9l-.6 1.3" fill="none" stroke="#006464" stroke-width=".18"/>
<path d="M35.6 62.2l12.7 6.4-12.7 6.3z" fill="#ffffc2"/>
<path d="M29.5 66h2v5.1h-2zM35.6 62.2l12.7 6.4-12.7 6.3z" fill="none" stroke="#840000" stroke-width=".25"/>
<path d="M30.5 64.8v1.2M30.5 71.1v1.3M33 66h2.6M33 73.7h2.6M33 63.5h2.6M33 71.1h2.6M40.6 61v3.8M40.6 72.4v3.8M43.2 71.1v5.1M48.3 68.6h2.5" fill="none" stroke="#840000" stroke-width=".18"/>
<path d="M30 66.5a.79 .79 0 0 1 1.3 0M36.1 73.8h1M40.7 69.8v1M42.9 78h.8l-.4 .5M43.7 78.7v.5" fill="none" stroke="#006464" stroke-width=".18"/>
<path d="M35.6 16.5l12.7 6.4-12.7 6.3z" fill="#ffffc2"/>
<path d="M35.6 16.5l12.7 6.4-12.7 6.3zM52.1 21.8h5v2.1h-5zM57.4 38.1h2v5.1h-2zM89.2 172.7h2v5.1h-2z" fill="none" stroke="#840000" stroke-width=".25"/>
<g fill="none" stroke="#840000" stroke-width=".18">
<path d="M33 17.8h2.6M40.6 15.2v3.9M33 20.3h2.6M33 27.9h2.6M33 25.4h2.6M40.6 26.7v3.8M43.2 25.4v5.1M48.3 22.9h3.8M55.6 27.9h2.8M57.1 22.9h1.3M58.4 36.8v1.3M64.8 36.8v2.8"/>
<path d="M58.4 43.2v1.3M64.8 41.7v2.8M90.2 171.5v1.2M90.2 177.8v1.3"/>
</g>
<path d="M36.1 28h1M40.7 24.1v1M42.9 32.3h.8l-.4 .5M43.7 32.9v.6" fill="none" stroke="#006464" stroke-width=".18"/>
<path d="M53.8 25.9v4.1M55.4 25.9v4.1M62.7 39.9h4.1M62.7 41.4h4.1" fill="none" stroke="#840000" stroke-width=".51"/>
<path d="M77.5 66l10.1 5.1-10.1 5.1z" fill="#ffffc2"/>
<path d="M77.5 66l10.1 5.1-10.1 5.1z" fill="none" stroke="#840000" stroke-width=".25"/>
<path d="M74.9 73.7h2.6M74.9 68.6h2.6M80 63.5v3.8M80 74.9v3.8M82.5 73.7v5M85.1 72.4v6.3M87.6 71.1h2.6" fill="none" stroke="#840000" stroke-width=".18"/>
<path d="M78 73.8h1M80.1 72.3v1M82.3 73h.5l-.5 .3h.5M82.3 72.8h.4M82.3 72.5h.4M82.3 72.2h.5M84.8 71.8h.5l-.5 .2h.5M84.8 71.5h.4M84.8 71.2h.4M84.8 71h.5M84.8 70.6h.5M84.1 80.3h.9l-.6 1.3" fill="none" stroke="#006464" stroke-width=".18"/>
<path d="M76.2 92.7l10.2-5.1v10.2z" fill="#ffffc2"/>
<path d="M176.8 36.8h2v5.1h-2zM76.2 92.7l10.2-5.1v10.2z" fill="none" stroke="#840000" stroke-width=".25"/>
<path d="M177.8 35.6v1.2M177.8 41.9v1.3M73.7 92.7h2.5M78.7 94v6.3M81.3 95.3v5M83.8 85.1v3.8M83.8 96.5v3.8M86.4 95.3h2.5M86.4 90.2h2.5" fill="none" stroke="#840000" stroke-width=".18"/>
<g fill="none" stroke="#006464" stroke-width=".18">
<path d="M177.5 37.1l.5 .5M178.4 37.1l-.5 .4M78.5 93.3h.5l-.5 .3h.5M78.5 93.1h.4M78.5 92.8h.4M78.5 92.6h.5M78.5 92.2h.5M81 94.6h.5l-.5 .3h.5M81 94.4h.4M81 94.1h.4M81 93.8h.5M83.9 93.9v1"/>
<path d="M84.9 95.3h.9"/>
</g>
<path d="M76.2 47l10.2-5.1v10.2z" fill="#ffffc2"/>
<path d="M76.2 47l10.2-5.1v10.2z" fill="none" stroke="#840000" stroke-width=".25"/>
<path d="M83.8 39.4v3.8M73.7 47h2.5M78.7 48.3v6.3M81.3 49.5v5.1M83.8 50.8v3.8M86.4 49.5h2.5M86.4 44.5h2.5" fill="none" stroke="#840000" stroke-width=".18"/>
<path d="M78.5 47.6h.5l-.5 .3h.5M78.5 47.4h.4M78.5 47.1h.4M78.5 46.8h.5M78.5 46.4h.5M81 48.9h.5l-.5 .3h.5M81 48.6h.4M81 48.4h.4M81 48.1h.5M83.9 48.2v1M84.9 49.6h.9" fill="none" stroke="#006464" stroke-width=".18"/>
<path d="M72.4 157.5l10.1 5.1-10.1 5z" fill="#ffffc2"/>
<path d="M96.5 70.1h5.1v2h-5.1zM106.7 70.1h5.1v2h-5.1zM94.2 95.3h2.1v5h-2.1zM94.2 81.3h2.1v5.1h-2.1zM61 159h5v2h-5zM72.4 157.5l10.1 5.1-10.1 5z" fill="none" stroke="#840000" stroke-width=".25"/>
<g fill="none" stroke="#840000" stroke-width=".18">
<path d="M95.2 71.1h1.3M101.6 71.1h1.3M105.4 71.1h1.3M111.8 71.1h1.2M115.6 76.2v2.8M119.1 64.8h2.8M95.2 80v1.3M95.2 86.4v1.2M95.2 94v1.3M115.6 81v2.8M95.2 100.3v1.3M74.9 154.9v3.9"/>
<path d="M59.7 160h1.3M65.8 165.1h2.8M66 160h1.3M69.8 165.1h2.6M69.8 160h2.6M74.9 166.4v3.8M77.5 165.1v5.1M80 163.8v6.4M82.5 162.6h2.6"/>
</g>
<g fill="none" stroke="#006464" stroke-width=".18">
<path d="M116.5 66h.4M116.5 65.3h.6M116.7 64.3h.7M114.8 82h.4M114.8 81.4h.6M63.4 164.7h.7M72.9 165.2h1M75 163.8v1M77.2 164.5h.5l-.5 .3h.5M77.2 164.2h.4M77.2 163.9h.4M77.2 163.7h.5"/>
<path d="M78.4 162.6h.7M79.1 171.8h.8l-.5 1.2M79.7 163.2h.5l-.5 .3h.5M79.7 162.9h.4M79.7 162.7h.4M79.7 162.4h.5M79.7 162h.5"/>
</g>
<path d="M113.5 79.2h4.1M117.3 62.7v4.1M118.9 62.7v4.1M113.5 80.8h4.1M64 163.1v4M65.5 163.1v4" fill="none" stroke="#840000" stroke-width=".51"/>
<path d="M156.7 43.2h3.3M156.7 48.3h3.3" fill="none" stroke="#ffffc2" stroke-width=".18"/>
<g fill="#ffffc2">
<path d="M156.7 48v.3z"/>
<path d="M154.9 41.3h10.2v8.9h-10.2z"/>
</g>
<path d="M170.2 30.5h2.8M175 30.5h2.8M156.2 44.4h1.1v2.8h-1.1zM156.7 47.2v1.1h3.3M156.7 43.4v.9M157.3 45.7l1-.5v1zM158.3 45.7h1.7M160 43.2h-3.3v.2M165.1 45.7h2.5M165.1 43.2h2.5M165.1 48.3h2.5" fill="none" stroke="#840000" stroke-width=".18"/>
<path d="M154.9 41.3h10.2v8.9h-10.2z" fill="none" stroke="#840000" stroke-width=".25"/>
<path d="M166.6 42.8h.7" fill="none" stroke="#a90000" stroke-width=".18"/>
<path d="M173.2 28.4v4.1M174.8 28.4v4.1" fill="none" stroke="#840000" stroke-width=".51"/>
<path d="M154.9 25.4l10.2 5.1-10.2 5.1z" fill="#ffffc2"/>
<path d="M133.6 34.3h2v5.1h-2zM137.2 26.9h5v2.1h-5zM154.9 25.4l10.2 5.1-10.2 5.1zM171.7 174h2v5.1h-2z" fill="none" stroke="#840000" stroke-width=".25"/>
<g fill="none" stroke="#840000" stroke-width=".18">
<path d="M134.6 33v1.3M134.6 39.4v1.2M135.9 27.9h1.3M142.2 27.9h1.3M144.8 36.8v2.8M152.4 33h2.5M152.4 27.9h2.5M157.5 22.9v3.8M157.5 34.3v3.8M160 33v5.1M162.6 31.8v6.3M165.1 30.5h2.5"/>
<path d="M144.8 41.7v2.8M172.7 172.7v1.3M172.7 179.1v1.2"/>
</g>
<g fill="none" stroke="#006464" stroke-width=".18">
<path d="M140.3 26.5h.7M155.5 33.1h.9M157.6 31.7v1M159.7 32.4h.5l-.5 .3h.5M159.7 32.1h.5M159.7 31.8h.5M159.7 31.6h.5M162.3 31.1h.5l-.5 .3h.5M162.3 30.9h.4M162.3 30.6h.4M162.3 30.3h.5M162.3 29.9h.5"/>
<path d="M163.9 23.7h.8l-.5 1.3M144 42.8h.4M144 42.2h.6M172.5 174.3l.4 .5M173.3 174.3l-.5 .4"/>
</g>
<path d="M142.7 39.9h4.1M142.7 41.4h4.1" fill="none" stroke="#840000" stroke-width=".51"/>
<path d="M151.6 180.3h3.3M151.6 185.4h3.3" fill="none" stroke="#ffffc2" stroke-width=".18"/>
<g fill="#ffffc2">
<path d="M151.6 185.2v.2z"/>
<path d="M149.9 178.4h10.1v8.9h-10.1z"/>
</g>
<g fill="none" stroke="#840000" stroke-width=".18">
<path d="M134.6 41.9v1.3M134.6 48.3v1.2M170.2 76.2h2.8M175 76.2h2.8M165.1 167.6h2.8M169.9 167.6h2.8M151.2 181.5h1v2.8h-1zM151.6 184.3v1.1h3.3M152.2 182.9l1-.5v1zM153.2 182.9h1.7M154.9 180.3h-3.3v1.2M160 182.9h2.6"/>
<path d="M160 180.3h2.6M160 185.4h2.6"/>
</g>
<path d="M133.6 43.2h2v5.1h-2zM149.9 178.4h10.1v8.9h-10.1z" fill="none" stroke="#840000" stroke-width=".25"/>
<path d="M161.5 179.9h.8" fill="none" stroke="#a90000" stroke-width=".18"/>
<path d="M173.2 74.2v4M174.8 74.2v4M168.1 165.6v4.1M169.7 165.6v4.1" fill="none" stroke="#840000" stroke-width=".51"/>
<path d="M172.3 75.3h.7" fill="none" stroke="#006464" stroke-width=".18"/>
<path d="M154.9 71.1l10.2 5.1-10.2 5.1z" fill="#ffffc2"/>
<path d="M154.9 71.1l10.2 5.1-10.2 5.1z" fill="none" stroke="#840000" stroke-width=".25"/>
<path d="M152.4 78.7h2.5M152.4 73.7h2.5M157.5 68.6v3.8M160 78.7v5.1M162.6 77.5v6.3M165.1 76.2h2.5M157.5 80v3.8" fill="none" stroke="#840000" stroke-width=".18"/>
<g fill="none" stroke="#006464" stroke-width=".18">
<path d="M155.5 78.8h.9M157.6 77.4v1M159.7 78.1h.5l-.5 .3h.5M159.7 77.9h.5M159.7 77.6h.5M159.7 77.3h.5M160.9 76h.8M162.3 76.8h.5l-.5 .3h.5M162.3 76.6h.4M162.3 76.3h.4M162.3 76.1h.5M162.3 75.6h.5"/>
<path d="M163.9 69.4h.8l-.5 1.3"/>
</g>
<path d="M121.9 68.6l10.2 5.1-10.2 5z" fill="#ffffc2"/>
<path d="M121.9 68.6l10.2 5.1-10.2 5z" fill="none" stroke="#840000" stroke-width=".25"/>
<path d="M119.4 76.2h2.5M119.4 71.1h2.5M124.5 66v3.9M124.5 77.5v3.8M127 76.2v5.1M129.5 74.9v6.4M132.1 73.7h2.5" fill="none" stroke="#840000" stroke-width=".18"/>
<path d="M122.4 76.3h1M124.6 74.9v1M126.7 75.6h.5l-.5 .3h.5M126.7 75.3h.4M126.7 75h.4M126.7 74.8h.5M129.3 74.3h.5l-.5 .3h.5M129.3 74h.4M129.3 73.8h.4M129.3 73.5h.5M129.3 73.1h.5M132.1 69.9h.9l-.6 1.3" fill="none" stroke="#006464" stroke-width=".18"/>
<path d="M149.9 162.6l10.1 5-10.1 5.1z" fill="#ffffc2"/>
<path d="M133.6 88.9h2v5.1h-2zM149.9 162.6l10.1 5-10.1 5.1z" fill="none" stroke="#840000" stroke-width=".25"/>
<path d="M134.6 87.6v1.3M134.6 94v1.3M144.8 82.6v2.7M144.8 87.4v2.8M147.3 170.2h2.6M147.3 165.1h2.6M152.4 160v3.8M152.4 171.5v3.8M154.9 170.2v5.1M157.5 168.9v6.4M160 167.6h2.6" fill="none" stroke="#840000" stroke-width=".18"/>
<g fill="none" stroke="#006464" stroke-width=".18">
<path d="M144 88.6h.4M144 88h.6M150.4 170.3h1M152.5 168.9v.9M154.7 169.5h.5l-.5 .3h.5M154.7 169.3h.4M154.7 169h.4M154.7 168.8h.5M157.2 168.3h.5l-.5 .3h.5M157.2 168h.4M157.2 167.7h.4M157.2 167.5h.5"/>
<path d="M157.2 167.1h.5M158.8 160.9h.9l-.6 1.2"/>
</g>
<path d="M142.7 87.1h4.1M142.7 85.6h4.1" fill="none" stroke="#840000" stroke-width=".51"/>
<path d="M77.5 111.8l10.1 5-10.1 5.1z" fill="#ffffc2"/>
<path d="M66 113.3h5.1v2h-5.1zM77.5 111.8l10.1 5-10.1 5.1z" fill="none" stroke="#840000" stroke-width=".25"/>
<path d="M64.8 114.3h1.2M70.9 119.4h2.8M71.1 114.3h1.3M74.9 119.4h2.6M74.9 114.3h2.6M80 109.2v3.8M82.5 119.4v5.1M85.1 118.1v6.4M87.6 116.8h2.6M80 120.7v3.8" fill="none" stroke="#840000" stroke-width=".18"/>
<path d="M78 119.5h1M80.1 118.1v.9M82.3 118.7h.5l-.5 .3h.5M82.3 118.5h.4M82.3 118.2h.4M82.3 118h.5M84.8 117.5h.5l-.5 .3h.5M84.8 117.2h.4M84.8 116.9h.4M84.8 116.7h.5M84.8 116.3h.5M84.1 126.1h.9l-.6 1.2" fill="none" stroke="#006464" stroke-width=".18"/>
<path d="M69.1 117.3v4.1M70.6 117.3v4.1" fill="none" stroke="#840000" stroke-width=".51"/>
<path d="M76.2 138.4l10.2-5v10.1z" fill="#ffffc2"/>
<path d="M133.6 80h2v5.1h-2zM76.2 138.4l10.2-5v10.1z" fill="none" stroke="#840000" stroke-width=".25"/>
<path d="M134.6 78.7v1.3M134.6 85.1v1.3M73.7 138.4h2.5M78.7 139.7v6.4M83.8 130.8v3.8M86.4 135.9h2.5M81.3 141v5.1M83.8 142.2v3.9M86.4 141h2.5" fill="none" stroke="#840000" stroke-width=".18"/>
<path d="M133.6 81.1h.8M78.5 139.1h.5l-.5 .3h.5M78.5 138.8h.4M78.5 138.5h.4M78.5 138.3h.5M78.5 137.9h.5M81 139.8h.4M81 139.6h.5M83.9 139.7v.9M81 140.3h.5l-.5 .3h.5M81 140.1h.4M84.9 141.1h.9" fill="none" stroke="#006464" stroke-width=".18"/>
<path d="M156.7 88.9h3.3M156.7 94h3.3" fill="none" stroke="#ffffc2" stroke-width=".18"/>
<g fill="#ffffc2">
<path d="M156.7 93.7v.3z"/>
<path d="M154.9 87h10.2v8.9h-10.2z"/>
</g>
<g fill="none" stroke="#840000" stroke-width=".18">
<path d="M33 17.8h2.6M40.6 15.2v3.9M119.1 19.1h2.8M33 25.4h2.6M33 27.9h2.6M33 20.3h2.6M40.6 26.7v3.8M43.2 25.4v5.1M48.3 22.9h3.8M55.6 27.9h2.8M57.1 22.9h1.3M119.4 30.5h2.5"/>
<path d="M119.4 25.4h2.5M124.5 20.3v3.8M124.5 31.8v3.8M127 30.5v5.1M129.5 29.2v6.4M132.1 27.9h2.5M134.6 33v1.3M134.6 39.4v1.2M33 71.1h2.6M33 73.7h2.6M33 66h2.6M33 63.5h2.6"/>
<path d="M40.6 61v3.8M40.6 72.4v3.8M43.2 71.1v5.1M48.3 68.6h3.8M55.6 73.7h2.8M57.1 68.6h1.3M119.1 64.8h2.8M119.4 76.2h2.5M119.4 71.1h2.5M124.5 66v3.9M124.5 77.5v3.8M127 76.2v5.1"/>
<path d="M129.5 74.9v6.4M132.1 73.7h2.5M134.6 78.7v1.3M134.6 85.1v1.3M156.2 90.1h1.1v2.8h-1.1zM156.7 92.9v1.1h3.3M157.3 91.4l1-.5v1zM158.3 91.4h1.7M160 88.9h-3.3v1.2M165.1 91.4h2.5M165.1 88.9h2.5M165.1 94h2.5"/>
<path d="M33 119.4h2.6M33 111.8h2.6M33 109.2h2.6M33 116.8h2.6M40.6 106.7v3.8M40.6 118.1v3.8M43.2 116.8v5.1M48.3 114.3h3.8M55.6 119.4h2.8M57.1 114.3h1.3M119.1 110.5h2.8M119.4 116.8h2.5"/>
<path d="M124.5 111.8v3.8M132.1 119.4h2.5M119.4 121.9h2.5M124.5 123.2v3.8M127 121.9v5.1M129.5 120.7v6.3M134.6 124.5v1.2M134.6 130.8v1.3M27.9 157.5h2.6M27.9 154.9h2.6M35.6 152.4v3.8M114 156.2h2.8"/>
<path d="M119.4 157.5v3.8M27.9 165.1h2.6M27.9 162.6h2.6M35.6 163.8v3.8M38.1 162.6v5M43.2 160h3.8M50.5 165.1h2.8M52.1 160h1.2M114.3 162.6h2.5M114.3 167.6h2.5M119.4 168.9v3.8M121.9 167.6v5.1"/>
<path d="M124.5 166.4v6.3M127 165.1h2.5M129.5 170.2v1.3M129.5 176.5v1.3"/>
</g>
<path d="M154.9 87h10.2v8.9h-10.2z" fill="none" stroke="#840000" stroke-width=".25"/>
<path d="M166.6 88.5h.7" fill="none" stroke="#a90000" stroke-width=".18"/>
<g fill="none" stroke="#0000c2" stroke-width=".18">
<path d="M19 16.5h3.9v149.9h-3.9zM224.8 90.2h2.5v2.5h-2.5zM227.5 88.2v1.1l.1 .2M242.1 88.7v.2l-.6 .2M242.7 88.6v.9M243.1 88.6l-.4 .3M223.5 128.3h6.4v12.7h-6.4zM228.7 126.7l.4 .1M229.1 126.7v1.1l-.3 .2M229.1 127.5l-.4 .1M235.8 126.7h.5M236 126.3v1.1l.3 .2"/>
<path d="M23.9 168.1l.6-.2v-.2l-.4-.1-.2 .2 .1 .6h.5"/>
</g>
<g fill="none" stroke="#009600" stroke-width=".18">
<path d="M21.6 17.8h11.4M30.5 19.1h2.5v1.2M80 15.2v2.6M91.4 15.2v24.2h-7.6M114.3 19.1h-10.2v6.3M121.9 19.1h12.7v13.9M124.5 15.2v5.1M157.5 15.2v7.7M21.6 27.9h11.4M33 25.4v1.3h-2.5M40.6 30.5v29.2M50.8 22.9v5"/>
<path d="M58.4 22.9h6.4v13.9M66 27.9h-7.6v8.9M72.4 22.9h2.5M73.7 22.9v5M74.9 27.9v8.9h15.3v-11.4h5v8.9M80 33v6.4h-8.9v20.3M102.9 25.4h2.5M113 25.4h6.4M115.6 25.4v5.1M115.6 38.1v20.3M119.4 30.5v10.1h15.2v1.3M124.5 35.6v24.1"/>
<path d="M134.6 27.9h1.3M143.5 27.9h8.9M144.8 27.9v8.9M152.4 33h-2.5v19.1h17.7v-3.8M157.5 38.1h-5.1v21.6h-137.2M167.6 30.5h2.6v12.7h-2.6M177.8 35.6v-5.1h10.2v100.3h38.1M58.4 44.5v2.5h15.3M64.8 44.5v11.4h24.1v-6.4M83.8 54.6v5.1M88.9 44.5h6.3M95.2 55.9v2.5h95.3v137.2h-100.3v-2.6"/>
<path d="M95.2 41.9v6.4M134.6 49.5v8.9M144.8 44.5v13.9M167.6 45.7h26.7v137.2h-31.7M177.8 43.2v15.2M17.8 61h139.7v7.6M21.6 73.7h11.4M21.6 63.5h11.4M30.5 64.8h2.5v1.2M33 71.1v1.3h-2.5M40.6 76.2v29.2M50.8 68.6v5.1"/>
<path d="M58.4 68.6h6.4v14M66 73.7h-7.6v8.9M72.4 68.6h2.5M73.7 68.6v5.1M74.9 73.7v8.9h15.3v-11.5h5v8.9M80 78.7v6.4h-8.9v20.3M80 61v2.5M91.4 61v24.1h-7.6M102.9 71.1h2.5M113 71.1h6.4M114.3 64.8h-10.2v6.3M115.6 71.1v5.1"/>
<path d="M119.4 76.2v10.2h15.2v1.2M121.9 64.8h12.7v13.9M124.5 61v5M134.6 73.7h1.3M143.5 73.7h8.9M144.8 73.7v8.9M152.4 78.7h-2.5v19.1h17.7v-3.8M167.6 76.2h2.6v12.7h-2.6M226.1 77.5h-34.3v-62.3h-174v137.2h134.6v7.6M226.1 74.9h-33.1v-60.9h-177.8v182.9h132.1v-21.6h5.1M58.4 90.2v2.5h15.3M64.8 90.2v11.4h24.1v-6.3"/>
<path d="M88.9 90.2h6.3M95.2 87.6v6.4M115.6 83.8v20.3M124.5 81.3v24.1M134.6 95.3v8.8M144.8 90.2v13.9M157.5 83.8h-5.1v21.6h-137.2M167.6 91.4h58.5M177.8 81.3v-5.1h7.6v57.2h40.7M177.8 88.9v15.2M190.5 80h35.6M17.8 106.7h139.7v7.6"/>
<path d="M21.6 119.4h11.4M21.6 109.2h11.4M30.5 110.5h2.5v1.3M33 116.8v1.3h-2.5M50.8 114.3v5.1M58.4 114.3h6.4v14M66 119.4h-7.6v8.9M72.4 114.3h2.5M73.7 114.3v5.1M74.9 119.4v8.9h15.3v-11.5h5v8.9M80 106.7v2.5M83.8 100.3v5.1"/>
<path d="M91.4 106.7v24.1h-7.6M95.2 101.6v2.5h95.3M102.9 116.8h2.5M113 116.8h6.4M114.3 110.5h-10.2v6.3M115.6 116.8v5.1M121.9 110.5h12.7v14M124.5 106.7v5.1M134.6 119.4h1.3M143.5 119.4h8.9M144.8 119.4v8.9M40.6 121.9v29.2"/>
<path d="M58.4 135.9v2.5h15.3M64.8 135.9v11.4h24.1v-6.3M80 124.5v6.3h-8.9v20.3M88.9 135.9h6.3M95.2 133.4v6.3M115.6 129.5v20.4M119.4 121.9v10.2h15.2v1.3M124.5 127v24.1M144.8 135.9v14M152.4 124.5h-2.5v19h17.7v-3.8M157.5 129.5h-5.1v21.6h-137.2M167.6 121.9h2.6v12.7h-2.6"/>
<path d="M167.6 137.2h26.7M177.8 127v-5.1h5.1v14h43.2M177.8 134.6v15.3M226.1 138.4h-43.2v29.2h-10.2v5.1M21.6 154.9h6.3M25.4 156.2h2.5v1.3M74.9 152.4v2.5M83.8 146.1v5M86.4 152.4v24.1h-7.7M95.2 147.3v2.6h95.3M109.2 156.2h-10.1v6.4M116.8 156.2h12.7v14"/>
<path d="M119.4 152.4v5.1M134.6 141v8.9M21.6 165.1h6.3M27.9 162.6v1.2h-2.5M35.6 167.6v29.3M45.7 160v5.1M53.3 160h6.4v14M61 165.1h-7.7v8.9M67.3 160h2.5M68.6 160v5.1M69.8 165.1v8.9h15.3v-11.4h5.1v8.9M74.9 170.2v6.3h-8.9v20.4"/>
<path d="M90.2 179.1v6.3M97.8 162.6h2.5M107.9 162.6h6.4M110.5 162.6v5M110.5 175.3v20.3M114.3 167.6v10.2h15.2v1.3M119.4 172.7v24.2M129.5 165.1h1.3M138.4 165.1h8.9M139.7 165.1v8.9M147.3 170.2h-2.5v19h17.8v-3.8M162.6 167.6h2.5v12.7h-2.5"/>
<path d="M53.3 181.6v2.6h15.3M59.7 181.6v11.4h24.1v-6.3M78.7 191.8v5.1M83.8 181.6h6.4M129.5 186.7v8.9M139.7 181.6v14M172.7 180.3v15.3"/>
</g>
<g fill="none" stroke="#000084" stroke-width=".18">
<path d="M42.6 29.9l1.2 1.2M43.8 29.9l-1.2 1.2M81.9 32.4l1.3 1.2M83.2 32.4l-1.3 1.2M84.5 32.4l1.2 1.2M85.7 32.4l-1.2 1.2M126.4 35l1.2 1.2M127.6 35l-1.2 1.2M128.9 35l1.2 1.2M130.1 35l-1.2 1.2M159.4 37.5l1.2 1.2M160.6 37.5l-1.2 1.2"/>
<path d="M162 37.5l1.2 1.2M163.2 37.5l-1.2 1.2M42.6 75.6l1.2 1.2M43.8 75.6l-1.2 1.2M81.9 78.1l1.3 1.2M83.2 78.1l-1.3 1.2M84.5 78.1l1.2 1.2M85.7 78.1l-1.2 1.2M126.4 80.7l1.2 1.2M127.6 80.7l-1.2 1.2M128.9 80.7l1.2 1.2M130.1 80.7l-1.2 1.2"/>
<path d="M159.4 83.2l1.2 1.2M160.6 83.2l-1.2 1.2M162 83.2l1.2 1.2M163.2 83.2l-1.2 1.2M225.5 90.8l1.2 1.2M226.7 90.8l-1.2 1.2M42.6 121.3l1.2 1.2M43.8 121.3l-1.2 1.2M81.9 123.9l1.3 1.2M83.2 123.9l-1.3 1.2M84.5 123.9l1.2 1.2M85.7 123.9l-1.2 1.2"/>
<path d="M126.4 126.4l1.2 1.2M127.6 126.4l-1.2 1.2M128.9 126.4l1.2 1.2M130.1 126.4l-1.2 1.2M159.4 128.9l1.2 1.2M160.6 128.9l-1.2 1.2M162 128.9l1.2 1.2M163.2 128.9l-1.2 1.2M225.5 137.8l1.2 1.2M225.5 135.3l1.2 1.2M225.5 132.7l1.2 1.3M225.5 130.2l1.2 1.2"/>
<path d="M226.7 137.8l-1.2 1.2M226.7 135.3l-1.2 1.2M226.7 132.7l-1.2 1.3M226.7 130.2l-1.2 1.2M78.1 145.4l1.2 1.3M79.3 145.4l-1.2 1.3M80.7 145.4l1.2 1.3M81.9 145.4l-1.2 1.3M37.5 167l1.2 1.2M38.7 167l-1.2 1.2M76.9 169.6l1.2 1.2M78.1 169.6l-1.2 1.2"/>
<path d="M79.4 169.6l1.2 1.2M80.6 169.6l-1.2 1.2M121.3 172.1l1.2 1.2M122.5 172.1l-1.2 1.2M123.9 172.1l1.2 1.2M125.1 172.1l-1.2 1.2M154.3 174.7l1.2 1.2M155.5 174.7l-1.2 1.2M156.9 174.7l1.2 1.2M158.1 174.7l-1.2 1.2"/>
</g>
<g fill="none" stroke="#006464" stroke-width=".18">
<path d="M116.5 19.6h.6M36.1 28h1M40.7 24.1v1M42.9 32.3h.8l-.4 .5M43.7 32.9v.6M116.5 20.2h.4M122.4 30.6h1M124.6 29.2v.9M126.7 29.8h.5l-.5 .3h.5M126.7 29.6h.4M126.7 29.3h.4M126.7 29.1h.5"/>
<path d="M129.3 28.6h.5l-.5 .3h.5M129.3 28.3h.4M129.3 28h.4M129.3 27.8h.5M129.3 27.4h.5M132.1 24.2h.9l-.6 1.3M36.1 73.8h1M40.7 69.8v1M42.9 78h.8l-.4 .5M43.7 78.7v.5M116.5 66h.4M116.5 65.3h.6"/>
<path d="M116.7 64.3h.7M122.4 76.3h1M124.6 74.9v1M126.7 75.6h.5l-.5 .3h.5M126.7 75.3h.4M126.7 75h.4M126.7 74.8h.5M129.3 74.3h.5l-.5 .3h.5M129.3 74h.4M129.3 73.8h.4M129.3 73.5h.5M129.3 73.1h.5"/>
<path d="M132.1 69.9h.9l-.6 1.3M133.6 81.1h.8M36.1 119.5h1M40.7 115.5v1M116.5 111.7h.4M116.5 111.1h.6M129.3 119.5h.4M129.3 119.8h.4M129.3 119.2h.5M129.3 118.8h.5M132.1 115.6h.9l-.6 1.3M42.9 123.8h.8l-.4 .5"/>
<path d="M43.7 124.4v.5M122.4 122h1M124.6 120.6v1M126.7 121.3h.5l-.5 .3h.5M126.7 121h.4M126.7 120.7h.4M126.7 120.5h.5M129.3 120h.5l-.5 .3h.5M111.4 157.4h.4M111.4 156.8h.6M31 165.2h1M35.7 161.2v1"/>
<path d="M37.9 169.5h.7l-.4 .5M38.6 170.1v.5M117.4 167.7h.9M119.5 166.3v1M121.6 167h.5l-.5 .3h.5M121.6 166.8h.5M121.6 166.5h.5M121.6 166.2h.5M124.2 165.2h.4M124.2 165.7h.5l-.5 .3h.5M124.2 165.5h.4M124.2 165h.5"/>
<path d="M124.2 164.5h.5M127.1 161.4h.8l-.5 1.2"/>
</g>
<g fill="#009600" stroke="#009600" stroke-width=".18">
<circle cx="53.3" cy="165.1" r=".46"/>
<circle cx="59.7" cy="160" r=".46"/>
<circle cx="45.7" cy="160" r=".46"/>
<circle cx="35.6" cy="196.9" r=".46"/>
<circle cx="59.7" cy="184.2" r=".46"/>
<circle cx="35.6" cy="152.4" r=".46"/>
<circle cx="110.5" cy="195.6" r=".46"/>
<circle cx="119.4" cy="196.9" r=".46"/>
<circle cx="86.4" cy="152.4" r=".46"/>
<circle cx="99.1" cy="162.6" r=".46"/>
<circle cx="110.5" cy="162.6" r=".46"/>
<circle cx="124.5" cy="151.1" r=".46"/>
<circle cx="119.4" cy="152.4" r=".46"/>
<circle cx="90.2" cy="181.6" r=".46"/>
<circle cx="78.7" cy="196.9" r=".46"/>
<circle cx="66" cy="196.9" r=".46"/>
<circle cx="85.1" cy="162.6" r=".46"/>
<circle cx="90.2" cy="162.6" r=".46"/>
<circle cx="74.9" cy="152.4" r=".46"/>
<circle cx="68.6" cy="160" r=".46"/>
<circle cx="172.7" cy="195.6" r=".46"/>
<circle cx="172.7" cy="167.6" r=".46"/>
<circle cx="165.1" cy="167.6" r=".46"/>
<circle cx="50.8" cy="114.3" r=".46"/>
<circle cx="64.8" cy="114.3" r=".46"/>
<circle cx="58.4" cy="119.4" r=".46"/>
<circle cx="17.8" cy="106.7" r=".46"/>
<circle cx="40.6" cy="151.1" r=".46"/>
<circle cx="64.8" cy="138.4" r=".46"/>
<circle cx="40.6" cy="106.7" r=".46"/>
<circle cx="129.5" cy="195.6" r=".46"/>
<circle cx="129.5" cy="177.8" r=".46"/>
<circle cx="139.7" cy="195.6" r=".46"/>
<circle cx="115.6" cy="25.4" r=".46"/>
<circle cx="124.5" cy="15.2" r=".46"/>
<circle cx="104.1" cy="25.4" r=".46"/>
<circle cx="144.8" cy="73.7" r=".46"/>
<circle cx="144.8" cy="104.1" r=".46"/>
<circle cx="134.6" cy="86.4" r=".46"/>
<circle cx="134.6" cy="104.1" r=".46"/>
<circle cx="115.6" cy="104.1" r=".46"/>
<circle cx="134.6" cy="73.7" r=".46"/>
<circle cx="144.8" cy="58.4" r=".46"/>
<circle cx="134.6" cy="58.4" r=".46"/>
<circle cx="134.6" cy="27.9" r=".46"/>
<circle cx="134.6" cy="40.6" r=".46"/>
<circle cx="144.8" cy="27.9" r=".46"/>
<circle cx="157.5" cy="15.2" r=".46"/>
<circle cx="115.6" cy="71.1" r=".46"/>
<circle cx="115.6" cy="58.4" r=".46"/>
<circle cx="124.5" cy="61" r=".46"/>
<circle cx="124.5" cy="59.7" r=".46"/>
<circle cx="104.1" cy="71.1" r=".46"/>
<circle cx="95.2" cy="44.5" r=".46"/>
<circle cx="83.8" cy="151.1" r=".46"/>
<circle cx="71.1" cy="151.1" r=".46"/>
<circle cx="95.2" cy="135.9" r=".46"/>
<circle cx="190.5" cy="80" r=".46"/>
<circle cx="190.5" cy="149.9" r=".46"/>
<circle cx="95.2" cy="116.8" r=".46"/>
<circle cx="73.7" cy="114.3" r=".46"/>
<circle cx="91.4" cy="106.7" r=".46"/>
<circle cx="90.2" cy="116.8" r=".46"/>
<circle cx="80" cy="106.7" r=".46"/>
<circle cx="83.8" cy="59.7" r=".46"/>
<circle cx="40.6" cy="61" r=".46"/>
<circle cx="50.8" cy="22.9" r=".46"/>
<circle cx="40.6" cy="15.2" r=".46"/>
<circle cx="40.6" cy="59.7" r=".46"/>
<circle cx="17.8" cy="61" r=".46"/>
<circle cx="15.2" cy="59.7" r=".46"/>
<circle cx="95.2" cy="90.2" r=".46"/>
<circle cx="95.2" cy="71.1" r=".46"/>
<circle cx="90.2" cy="71.1" r=".46"/>
<circle cx="73.7" cy="68.6" r=".46"/>
<circle cx="91.4" cy="61" r=".46"/>
<circle cx="80" cy="61" r=".46"/>
<circle cx="64.8" cy="47" r=".46"/>
<circle cx="64.8" cy="22.9" r=".46"/>
<circle cx="58.4" cy="27.9" r=".46"/>
<circle cx="71.1" cy="59.7" r=".46"/>
<circle cx="15.2" cy="105.4" r=".46"/>
<circle cx="40.6" cy="105.4" r=".46"/>
<circle cx="15.2" cy="151.1" r=".46"/>
<circle cx="58.4" cy="73.7" r=".46"/>
<circle cx="71.1" cy="105.4" r=".46"/>
<circle cx="83.8" cy="105.4" r=".46"/>
<circle cx="64.8" cy="68.6" r=".46"/>
<circle cx="64.8" cy="92.7" r=".46"/>
<circle cx="50.8" cy="68.6" r=".46"/>
<circle cx="90.2" cy="25.4" r=".46"/>
<circle cx="95.2" cy="25.4" r=".46"/>
<circle cx="73.7" cy="22.9" r=".46"/>
<circle cx="80" cy="15.2" r=".46"/>
<circle cx="91.4" cy="15.2" r=".46"/>
<circle cx="177.8" cy="76.2" r=".46"/>
<circle cx="177.8" cy="58.4" r=".46"/>
<circle cx="170.2" cy="30.5" r=".46"/>
<circle cx="177.8" cy="30.5" r=".46"/>
<circle cx="134.6" cy="119.4" r=".46"/>
<circle cx="124.5" cy="105.4" r=".46"/>
<circle cx="124.5" cy="106.7" r=".46"/>
<circle cx="115.6" cy="116.8" r=".46"/>
<circle cx="115.6" cy="149.9" r=".46"/>
<circle cx="104.1" cy="116.8" r=".46"/>
<circle cx="129.5" cy="165.1" r=".46"/>
<circle cx="139.7" cy="165.1" r=".46"/>
<circle cx="177.8" cy="149.9" r=".46"/>
<circle cx="194.3" cy="137.2" r=".46"/>
<circle cx="177.8" cy="121.9" r=".46"/>
<circle cx="190.5" cy="104.1" r=".46"/>
<circle cx="134.6" cy="149.9" r=".46"/>
<circle cx="134.6" cy="132.1" r=".46"/>
<circle cx="144.8" cy="149.9" r=".46"/>
<circle cx="144.8" cy="119.4" r=".46"/>
<circle cx="170.2" cy="121.9" r=".46"/>
<circle cx="194.3" cy="91.4" r=".46"/>
<circle cx="177.8" cy="104.1" r=".46"/>
<circle cx="170.2" cy="76.2" r=".46"/>
</g>
<use href="#words"/>
</svg>
